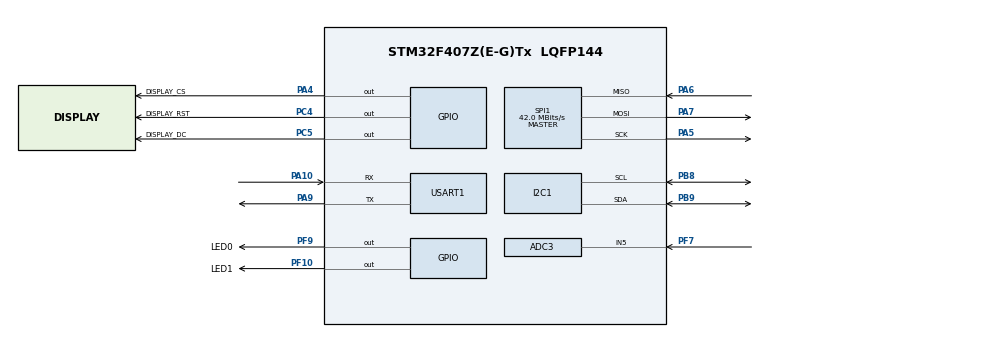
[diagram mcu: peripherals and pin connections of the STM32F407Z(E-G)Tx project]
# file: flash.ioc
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ADC3.Channel-1\#ChannelRegularConversion=ADC_CHANNEL_5
ADC3.EnableAnalogWatchDog=false
ADC3.InjNumberOfConversion=0
ADC3.NbrOfConversion=1
ADC3.NbrOfConversionFlag=1
ADC3.Rank-1\#ChannelRegularConversion=1
ADC3.SamplingTime-1\#ChannelRegularConversion=ADC_SAMPLETIME_480CYCLES
Dma.I2C1_RX.2.Direction=DMA_PERIPH_TO_MEMORY
Dma.I2C1_RX.2.FIFOMode=DMA_FIFOMODE_DISABLE
Dma.I2C1_RX.2.Instance=DMA1_Stream0
Dma.I2C1_RX.2.MemDataAlignment=DMA_MDATAALIGN_BYTE
Dma.I2C1_RX.2.MemInc=DMA_MINC_ENABLE
Dma.I2C1_RX.2.Mode=DMA_NORMAL
Dma.I2C1_RX.2.PeriphDataAlignment=DMA_PDATAALIGN_BYTE
Dma.I2C1_RX.2.PeriphInc=DMA_PINC_DISABLE
Dma.I2C1_RX.2.Priority=DMA_PRIORITY_VERY_HIGH
Dma.I2C1_TX.3.Direction=DMA_MEMORY_TO_PERIPH
Dma.I2C1_TX.3.FIFOMode=DMA_FIFOMODE_DISABLE
Dma.I2C1_TX.3.Instance=DMA1_Stream6
Dma.I2C1_TX.3.MemDataAlignment=DMA_MDATAALIGN_BYTE
Dma.I2C1_TX.3.MemInc=DMA_MINC_ENABLE
Dma.I2C1_TX.3.Mode=DMA_NORMAL
Dma.I2C1_TX.3.PeriphDataAlignment=DMA_PDATAALIGN_BYTE
Dma.I2C1_TX.3.PeriphInc=DMA_PINC_DISABLE
Dma.I2C1_TX.3.Priority=DMA_PRIORITY_VERY_HIGH
Dma.Request0=USART1_RX
Dma.Request1=USART1_TX
Dma.Request2=I2C1_RX
Dma.Request3=I2C1_TX
Dma.Request4=SPI1_TX
Dma.Request5=SPI1_RX
Dma.SPI1_RX.5.Direction=DMA_PERIPH_TO_MEMORY
Dma.SPI1_RX.5.FIFOMode=DMA_FIFOMODE_DISABLE
Dma.SPI1_RX.5.Instance=DMA2_Stream0
Dma.SPI1_RX.5.MemDataAlignment=DMA_MDATAALIGN_BYTE
Dma.SPI1_RX.5.MemInc=DMA_MINC_ENABLE
Dma.SPI1_RX.5.Mode=DMA_NORMAL
Dma.SPI1_RX.5.PeriphDataAlignment=DMA_PDATAALIGN_BYTE
Dma.SPI1_RX.5.PeriphInc=DMA_PINC_DISABLE
Dma.SPI1_RX.5.Priority=DMA_PRIORITY_VERY_HIGH
Dma.SPI1_TX.4.Direction=DMA_MEMORY_TO_PERIPH
Dma.SPI1_TX.4.FIFOMode=DMA_FIFOMODE_DISABLE
Dma.SPI1_TX.4.Instance=DMA2_Stream3
Dma.SPI1_TX.4.MemDataAlignment=DMA_MDATAALIGN_BYTE
Dma.SPI1_TX.4.MemInc=DMA_MINC_ENABLE
Dma.SPI1_TX.4.Mode=DMA_NORMAL
Dma.SPI1_TX.4.PeriphDataAlignment=DMA_PDATAALIGN_BYTE
Dma.SPI1_TX.4.PeriphInc=DMA_PINC_DISABLE
Dma.SPI1_TX.4.Priority=DMA_PRIORITY_VERY_HIGH
Dma.USART1_RX.0.Direction=DMA_PERIPH_TO_MEMORY
Dma.USART1_RX.0.FIFOMode=DMA_FIFOMODE_DISABLE
Dma.USART1_RX.0.Instance=DMA2_Stream2
Dma.USART1_RX.0.MemDataAlignment=DMA_MDATAALIGN_BYTE
Dma.USART1_RX.0.MemInc=DMA_MINC_ENABLE
Dma.USART1_RX.0.Mode=DMA_NORMAL
Dma.USART1_RX.0.PeriphDataAlignment=DMA_PDATAALIGN_BYTE
Dma.USART1_RX.0.PeriphInc=DMA_PINC_DISABLE
Dma.USART1_RX.0.Priority=DMA_PRIORITY_VERY_HIGH
Dma.USART1_TX.1.Direction=DMA_MEMORY_TO_PERIPH
Dma.USART1_TX.1.FIFOMode=DMA_FIFOMODE_DISABLE
Dma.USART1_TX.1.Instance=DMA2_Stream7
Dma.USART1_TX.1.MemDataAlignment=DMA_MDATAALIGN_BYTE
Dma.USART1_TX.1.MemInc=DMA_MINC_ENABLE
Dma.USART1_TX.1.Mode=DMA_NORMAL
Dma.USART1_TX.1.PeriphDataAlignment=DMA_PDATAALIGN_BYTE
Dma.USART1_TX.1.PeriphInc=DMA_PINC_DISABLE
Dma.USART1_TX.1.Priority=DMA_PRIORITY_VERY_HIGH
I2C1.GeneralCallMode=I2C_GENERALCALL_DISABLE
I2C1.I2C_Mode=I2C_Fast
I2C1.NoStretchMode=I2C_NOSTRETCH_DISABLE
I2C1.OwnAddress=10
Mcu.Family=STM32F4
Mcu.Name=STM32F407Z(E-G)Tx
Mcu.Package=LQFP144
NVIC.DMA1_Stream0_IRQn=true\:0\:0\:true\:false\:true\:false\:true\:true
NVIC.DMA1_Stream6_IRQn=true\:0\:0\:true\:false\:true\:false\:true\:true
NVIC.DMA2_Stream0_IRQn=true\:0\:0\:false\:false\:true\:false\:true\:true
NVIC.DMA2_Stream2_IRQn=true\:0\:0\:true\:false\:true\:false\:true\:true
NVIC.DMA2_Stream3_IRQn=true\:0\:0\:false\:false\:true\:false\:true\:true
NVIC.DMA2_Stream7_IRQn=true\:0\:0\:true\:false\:true\:false\:true\:true
NVIC.I2C1_ER_IRQn=true\:2\:0\:true\:false\:true\:true\:true\:true
NVIC.I2C1_EV_IRQn=true\:2\:0\:true\:false\:true\:true\:true\:true
NVIC.PriorityGroup=NVIC_PRIORITYGROUP_4
NVIC.SPI1_IRQn=true\:0\:0\:false\:false\:true\:true\:true\:true
NVIC.USART1_IRQn=true\:0\:0\:true\:false\:true\:true\:true\:true
PA10.Mode=Asynchronous
PA10.Signal=USART1_RX
PA4.GPIO_Label=DISPLAY_CS
PA4.GPIO_Speed=GPIO_SPEED_FREQ_MEDIUM
PA4.Signal=GPIO_Output
PA5.Mode=Full_Duplex_Master
PA5.Signal=SPI1_SCK
PA6.Mode=Full_Duplex_Master
PA6.Signal=SPI1_MISO
PA7.Mode=Full_Duplex_Master
PA7.Signal=SPI1_MOSI
PA9.Mode=Asynchronous
PA9.Signal=USART1_TX
PB8.GPIO_Pu=GPIO_PULLUP
PB8.Mode=I2C
PB8.Signal=I2C1_SCL
PB9.GPIO_Pu=GPIO_PULLUP
PB9.Mode=I2C
PB9.Signal=I2C1_SDA
PC14-OSC32_IN.Mode=LSE-External-Oscillator
PC14-OSC32_IN.Signal=RCC_OSC32_IN
PC15-OSC32_OUT.Mode=LSE-External-Oscillator
PC15-OSC32_OUT.Signal=RCC_OSC32_OUT
PC4.GPIO_Label=DISPLAY_RST
PC4.GPIO_Speed=GPIO_SPEED_FREQ_MEDIUM
PC4.Signal=GPIO_Output
PC5.GPIO_Label=DISPLAY_DC
PC5.GPIO_Speed=GPIO_SPEED_FREQ_MEDIUM
PC5.Signal=GPIO_Output
PF10.GPIO_Label=LED1
PF10.GPIO_Speed=GPIO_SPEED_FREQ_MEDIUM
PF10.PinState=GPIO_PIN_SET
PF10.Signal=GPIO_Output
PF7.Mode=IN5
PF7.Signal=ADC3_IN5
PF9.GPIO_Label=LED0
PF9.GPIO_Speed=GPIO_SPEED_FREQ_MEDIUM
PF9.PinState=GPIO_PIN_SET
PF9.Signal=GPIO_Output
PH0-OSC_IN.Mode=HSE-External-Oscillator
PH0-OSC_IN.Signal=RCC_OSC_IN
PH1-OSC_OUT.Mode=HSE-External-Oscillator
PH1-OSC_OUT.Signal=RCC_OSC_OUT
ProjectManager.HeapSize=0x200
ProjectManager.StackSize=0x400
ProjectManager.TargetToolchain=STM32CubeIDE
RCC.48MHZClocksFreq_Value=84000000
RCC.AHBFreq_Value=168000000
RCC.APB1CLKDivider=RCC_HCLK_DIV4
RCC.APB1Freq_Value=42000000
RCC.APB1TimFreq_Value=84000000
RCC.APB2CLKDivider=RCC_HCLK_DIV2
RCC.APB2Freq_Value=84000000
RCC.APB2TimFreq_Value=168000000
RCC.CortexFreq_Value=168000000
RCC.HCLKFreq_Value=168000000
RCC.HSE_VALUE=8000000
RCC.HSI_VALUE=16000000
RCC.PLLM=8
RCC.PLLN=168
RCC.SYSCLKFreq_VALUE=168000000
RCC.SYSCLKSource=RCC_SYSCLKSOURCE_PLLCLK
RCC.VCOOutputFreq_Value=336000000
SPI1.BaudRatePrescaler=SPI_BAUDRATEPRESCALER_2
SPI1.CLKPolarity=SPI_POLARITY_HIGH
SPI1.CalculateBaudRate=42.0 MBits/s
SPI1.Direction=SPI_DIRECTION_2LINES
SPI1.Mode=SPI_MODE_MASTER
SPI1.TIMode=SPI_TIMODE_DISABLE
SPI1.VirtualType=VM_MASTER
USART1.VirtualMode=VM_ASYNC
board=custom

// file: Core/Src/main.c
/* USER CODE BEGIN Header */
/**
  ******************************************************************************
  * @file           : main.c
  * @brief          : Main program body
  ******************************************************************************
  * @attention
  *
  * Copyright (c) 2025 STMicroelectronics.
  * All rights reserved.
  *
  * This software is licensed under terms that can be found in the LICENSE file
  * in the root directory of this software component.
  * If no LICENSE file comes with this software, it is provided AS-IS.
  *
  ******************************************************************************
  */
/* USER CODE END Header */
#include "main.h"
#include "adc.h"
#include "dma.h"
#include "i2c.h"
#include "spi.h"
#include "usart.h"
#include "gpio.h"

/* USER CODE BEGIN Includes */

#include "app_main.h"

/* USER CODE END Includes */

void SystemClock_Config(void);

int main(void)
{
  /* USER CODE BEGIN 1 */
  app_main.on_init();
  /* USER CODE END 1 */

  /* MCU Configuration--------------------------------------------------------*/

  /* Reset of all peripherals, Initializes the Flash interface and the Systick. */
  HAL_Init();

  /* Configure the system clock */
  SystemClock_Config();

  /* Initialize all configured peripherals */
  MX_GPIO_Init();
  MX_DMA_Init();
  MX_USART1_UART_Init();
  MX_ADC3_Init();
  MX_I2C1_Init();
  MX_SPI1_Init();
  /* USER CODE BEGIN 2 */
  app_main.on_begin();
  /* USER CODE END 2 */

  /* Infinite loop */
  /* USER CODE BEGIN WHILE */
  app_main.on_start();
  while (1)
  {
    if (app_main.on_loop())break;
    /* USER CODE END WHILE */

    /* USER CODE BEGIN 3 */
  }
  app_main.on_end();
  /* USER CODE END 3 */
}

void SystemClock_Config(void)
{
  RCC_OscInitTypeDef RCC_OscInitStruct = {0};
  RCC_ClkInitTypeDef RCC_ClkInitStruct = {0};

  /** Configure the main internal regulator output voltage
  */
  __HAL_RCC_PWR_CLK_ENABLE();
  __HAL_PWR_VOLTAGESCALING_CONFIG(PWR_REGULATOR_VOLTAGE_SCALE1);

  /** Initializes the RCC Oscillators according to the specified parameters
  * in the RCC_OscInitTypeDef structure.
  */
  RCC_OscInitStruct.OscillatorType = RCC_OSCILLATORTYPE_HSI;
  RCC_OscInitStruct.HSIState = RCC_HSI_ON;
  RCC_OscInitStruct.HSICalibrationValue = RCC_HSICALIBRATION_DEFAULT;
  RCC_OscInitStruct.PLL.PLLState = RCC_PLL_ON;
  RCC_OscInitStruct.PLL.PLLSource = RCC_PLLSOURCE_HSI;
  RCC_OscInitStruct.PLL.PLLM = 8;
  RCC_OscInitStruct.PLL.PLLN = 168;
  RCC_OscInitStruct.PLL.PLLP = RCC_PLLP_DIV2;
  RCC_OscInitStruct.PLL.PLLQ = 4;
  if (HAL_RCC_OscConfig(&RCC_OscInitStruct) != HAL_OK)
  {
    Error_Handler();
  }

  /** Initializes the CPU, AHB and APB buses clocks
  */
  RCC_ClkInitStruct.ClockType = RCC_CLOCKTYPE_HCLK|RCC_CLOCKTYPE_SYSCLK
                              |RCC_CLOCKTYPE_PCLK1|RCC_CLOCKTYPE_PCLK2;
  RCC_ClkInitStruct.SYSCLKSource = RCC_SYSCLKSOURCE_PLLCLK;
  RCC_ClkInitStruct.AHBCLKDivider = RCC_SYSCLK_DIV1;
  RCC_ClkInitStruct.APB1CLKDivider = RCC_HCLK_DIV4;
  // RCC_ClkInitStruct.APB2CLKDivider = RCC_HCLK_DIV2;
  RCC_ClkInitStruct.APB2CLKDivider = RCC_HCLK_DIV1;

  if (HAL_RCC_ClockConfig(&RCC_ClkInitStruct, FLASH_LATENCY_5) != HAL_OK)
  {
    Error_Handler();
  }
}

void Error_Handler(void)
{
  __disable_irq();
  while (1)
  {
  }
}
